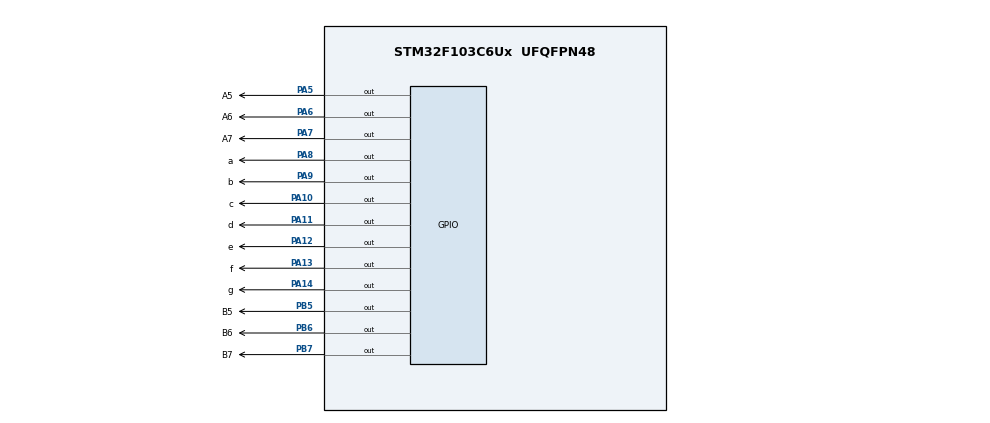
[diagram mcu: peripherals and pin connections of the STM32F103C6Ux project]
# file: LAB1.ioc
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Mcu.Family=STM32F1
Mcu.Name=STM32F103C6Ux
Mcu.Package=UFQFPN48
NVIC.PriorityGroup=NVIC_PRIORITYGROUP_4
PA10.GPIO_Label=c
PA10.Signal=GPIO_Output
PA11.GPIO_Label=d
PA11.Signal=GPIO_Output
PA12.GPIO_Label=e
PA12.Signal=GPIO_Output
PA13.GPIO_Label=f
PA13.Signal=GPIO_Output
PA14.GPIO_Label=g
PA14.Signal=GPIO_Output
PA5.GPIO_Label=A5
PA5.Signal=GPIO_Output
PA6.GPIO_Label=A6
PA6.Signal=GPIO_Output
PA7.GPIO_Label=A7
PA7.Signal=GPIO_Output
PA8.GPIO_Label=a
PA8.Signal=GPIO_Output
PA9.GPIO_Label=b
PA9.Signal=GPIO_Output
PB5.GPIO_Label=B5
PB5.Signal=GPIO_Output
PB6.GPIO_Label=B6
PB6.Signal=GPIO_Output
PB7.GPIO_Label=B7
PB7.Signal=GPIO_Output
ProjectManager.HeapSize=0x200
ProjectManager.StackSize=0x400
ProjectManager.TargetToolchain=STM32CubeIDE
RCC.APB1Freq_Value=8000000
RCC.APB2Freq_Value=8000000
VP_SYS_VS_ND.Mode=No_Debug
board=custom

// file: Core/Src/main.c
/* USER CODE BEGIN Header */
/**
  ******************************************************************************
  * @file           : main.c
  * @brief          : Main program body
  ******************************************************************************
  * @attention
  *
  * <h2><center>&copy; Copyright (c) 2023 STMicroelectronics.
  * All rights reserved.</center></h2>
  *
  * This software component is licensed by ST under BSD 3-Clause license,
  * the "License"; You may not use this file except in compliance with the
  * License. You may obtain a copy of the License at:
  *                        opensource.org/licenses/BSD-3-Clause
  *
  ******************************************************************************
  */
/* USER CODE END Header */
#include "main.h"

void SystemClock_Config(void);
static void MX_GPIO_Init(void);
/* USER CODE BEGIN PFP */
void clearAllClock(){
	HAL_GPIO_WritePin(GPIOA, GPIO_PIN_All, 1);
}
void setNumberOnClock(int num){
	switch(num){
	case 0:
		HAL_GPIO_WritePin(GPIOA, GPIO_PIN_4, 0);
		break;
	case 1:
		HAL_GPIO_WritePin(GPIOA, GPIO_PIN_5, 0);
		break;
	case 2:
		HAL_GPIO_WritePin(GPIOA, GPIO_PIN_6, 0);
		break;
	case 3:
		HAL_GPIO_WritePin(GPIOA, GPIO_PIN_7, 0);
		break;
	case 4:
		HAL_GPIO_WritePin(GPIOA, GPIO_PIN_8, 0);
		break;
	case 5:
		HAL_GPIO_WritePin(GPIOA, GPIO_PIN_9, 0);
		break;
	case 6:
		HAL_GPIO_WritePin(GPIOA, GPIO_PIN_10, 0);
		break;
	case 7:
		HAL_GPIO_WritePin(GPIOA, GPIO_PIN_11, 0);
		break;
	case 8:
		HAL_GPIO_WritePin(GPIOA, GPIO_PIN_12, 0);
		break;
	case 9:
		HAL_GPIO_WritePin(GPIOA, GPIO_PIN_13, 0);
		break;
	case 10:
		HAL_GPIO_WritePin(GPIOA, GPIO_PIN_14, 0);
		break;
	default:
		HAL_GPIO_WritePin(GPIOA, GPIO_PIN_15, 0);
	}
}
void clearNumberOnClock(int num){
	switch(num){
	case 0:
		HAL_GPIO_WritePin(GPIOA, GPIO_PIN_4, 1);
		break;
	case 1:
		HAL_GPIO_WritePin(GPIOA, GPIO_PIN_5, 1);
		break;
	case 2:
		HAL_GPIO_WritePin(GPIOA, GPIO_PIN_6, 1);
		break;
	case 3:
		HAL_GPIO_WritePin(GPIOA, GPIO_PIN_7, 1);
		break;
	case 4:
		HAL_GPIO_WritePin(GPIOA, GPIO_PIN_8, 1);
		break;
	case 5:
		HAL_GPIO_WritePin(GPIOA, GPIO_PIN_9, 1);
		break;
	case 6:
		HAL_GPIO_WritePin(GPIOA, GPIO_PIN_10, 1);
		break;
	case 7:
		HAL_GPIO_WritePin(GPIOA, GPIO_PIN_11, 1);
		break;
	case 8:
		HAL_GPIO_WritePin(GPIOA, GPIO_PIN_12, 1);
		break;
	case 9:
		HAL_GPIO_WritePin(GPIOA, GPIO_PIN_13, 1);
		break;
	case 10:
		HAL_GPIO_WritePin(GPIOA, GPIO_PIN_14, 1);
		break;
	default:
		HAL_GPIO_WritePin(GPIOA, GPIO_PIN_15, 1);
	}
}
/* USER CODE END PFP */

int main(void)
{

  /* MCU Configuration--------------------------------------------------------*/

  /* Reset of all peripherals, Initializes the Flash interface and the Systick. */
  HAL_Init();

  /* Configure the system clock */
  SystemClock_Config();

  /* Initialize all configured peripherals */
  MX_GPIO_Init();
  int hour=0,minute=0,second=0;
  setNumberOnClock(hour);
  /* Infinite loop */
  while (1)
  {
	  clearAllClock();
	  if(second==60){
		  second=0;
		  minute++;
	  }
	  if(minute==60){
		  minute=0;
		  hour++;
	  }
	  if(hour=12){
		  hour=0;
	  }
	  setNumberOnClock(second/5);
	  setNumberOnClock(minute/5);
	  setNumberOnClock(hour);
	  second++;
	  HAL_Delay(1000);
  }
}

void SystemClock_Config(void)
{
  RCC_OscInitTypeDef RCC_OscInitStruct = {0};
  RCC_ClkInitTypeDef RCC_ClkInitStruct = {0};

  /** Initializes the RCC Oscillators according to the specified parameters
  * in the RCC_OscInitTypeDef structure.
  */
  RCC_OscInitStruct.OscillatorType = RCC_OSCILLATORTYPE_HSI;
  RCC_OscInitStruct.HSIState = RCC_HSI_ON;
  RCC_OscInitStruct.HSICalibrationValue = RCC_HSICALIBRATION_DEFAULT;
  RCC_OscInitStruct.PLL.PLLState = RCC_PLL_NONE;
  if (HAL_RCC_OscConfig(&RCC_OscInitStruct) != HAL_OK)
  {
    Error_Handler();
  }
  /** Initializes the CPU, AHB and APB buses clocks
  */
  RCC_ClkInitStruct.ClockType = RCC_CLOCKTYPE_HCLK|RCC_CLOCKTYPE_SYSCLK
                              |RCC_CLOCKTYPE_PCLK1|RCC_CLOCKTYPE_PCLK2;
  RCC_ClkInitStruct.SYSCLKSource = RCC_SYSCLKSOURCE_HSI;
  RCC_ClkInitStruct.AHBCLKDivider = RCC_SYSCLK_DIV1;
  RCC_ClkInitStruct.APB1CLKDivider = RCC_HCLK_DIV1;
  RCC_ClkInitStruct.APB2CLKDivider = RCC_HCLK_DIV1;

  if (HAL_RCC_ClockConfig(&RCC_ClkInitStruct, FLASH_LATENCY_0) != HAL_OK)
  {
    Error_Handler();
  }
}

static void MX_GPIO_Init(void)
{
  GPIO_InitTypeDef GPIO_InitStruct = {0};

  /* GPIO Ports Clock Enable */
  __HAL_RCC_GPIOA_CLK_ENABLE();

  /*Configure GPIO pin Output Level */
  HAL_GPIO_WritePin(GPIOA, GPIO_PIN_4|GPIO_PIN_5|GPIO_PIN_6|GPIO_PIN_7
                          |GPIO_PIN_8|GPIO_PIN_9|GPIO_PIN_10|GPIO_PIN_11
                          |GPIO_PIN_12|GPIO_PIN_13|GPIO_PIN_14|GPIO_PIN_15, GPIO_PIN_RESET);

  /*Configure GPIO pins : PA4 PA5 PA6 PA7
                           PA8 PA9 PA10 PA11
                           PA12 PA13 PA14 PA15 */
  GPIO_InitStruct.Pin = GPIO_PIN_4|GPIO_PIN_5|GPIO_PIN_6|GPIO_PIN_7
                          |GPIO_PIN_8|GPIO_PIN_9|GPIO_PIN_10|GPIO_PIN_11
                          |GPIO_PIN_12|GPIO_PIN_13|GPIO_PIN_14|GPIO_PIN_15;
  GPIO_InitStruct.Mode = GPIO_MODE_OUTPUT_PP;
  GPIO_InitStruct.Pull = GPIO_NOPULL;
  GPIO_InitStruct.Speed = GPIO_SPEED_FREQ_LOW;
  HAL_GPIO_Init(GPIOA, &GPIO_InitStruct);

}

void Error_Handler(void)
{
  __disable_irq();
  while (1)
  {
  }
}

/************************ (C) COPYRIGHT STMicroelectronics *****END OF FILE****/
